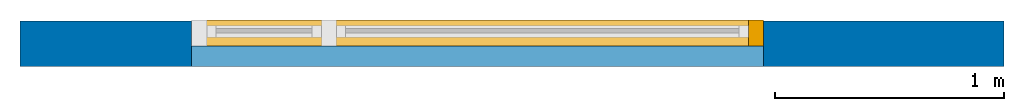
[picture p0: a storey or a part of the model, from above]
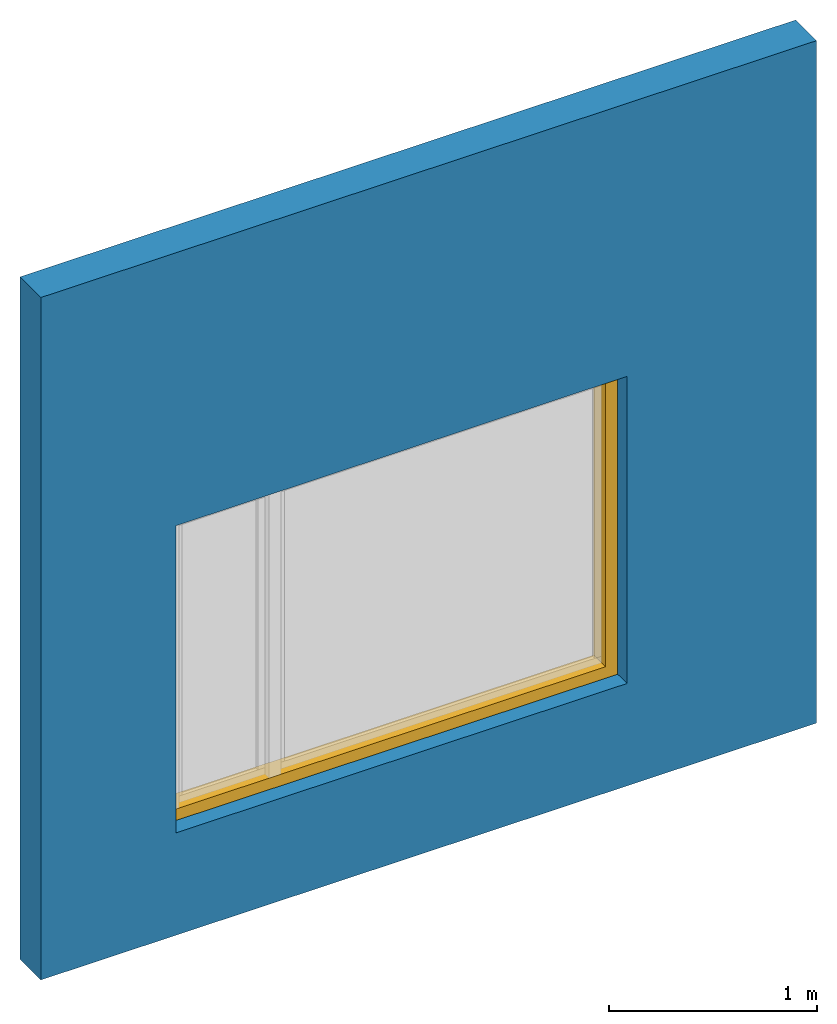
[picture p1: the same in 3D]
Properties of the parts of a building model (IFC2X3)

# File
Description: ViewDefinition [CoordinationView_V2.0]
Time: 2013-11-18T13:30:34
Written by: The EXPRESS Data Manager Version 5.01.0100.02.64mod : 6 Jun 2012
Made in: 20130308_1515(x64) - Exporter 3.5.0.0 - Alternate UI 2.5.0.0
Comment: STEP Physical File produced by: The EXPRESS Data Manager Version 5.01.0100.02.64mod : 6 Jun 2012 * Module: EDMstepFileFactory/EDMstandAlone * Creation date: Mon Nov 18 13:30:34 2013 * Host: MDR_LPTP_BTO * Database: C:\Users\Martijn\AppData\Local\Temp\{63A8A632-8D2A-48E5-82E8-79CE2EC71F87}\ifc * Database version: 5507 * Database creation date: Mon Nov 18 13:30:31 2013 * Schema: IFC2X3 * Model: DataRepository.ifc * Model creation date: Mon Nov 18 13:30:31 2013 * Header model: DataRepository.ifc_HeaderModel * Header model creation date: Mon Nov 18 13:30:31 2013 * EDMuser: sdai-user * EDMgroup: sdai-group * License ID and type: 5605 : Permanent license. Expiry date: * EDMstepFileFactory options: 020000

# IfcProject
LongName: E:\MdR Advies\Google Drive\005_Dropbox\Dropbox\RevitGG\RevitGG - DRS\WIP v1.1\test_export_window.ifc

# IfcSite, Default
RefLatitude: 42, 24, 53, 508911; RefLongitude: -71, -15, -29, -58837; RefElevation: 0 mm

# IfcBuilding
Pset_BuildingCommon - NumberOfStoreys: 1

# IfcBuildingStorey, Level 1
LongName: Level 1; Elevation: 0 mm

# IfcBuildingElementProxy: 30_GM_LB_bovendorpel, 30_GM_LB_bovendorpel:30_GM_LB_bovendorpel:16037
In: Level 1
Pset_BuildingElementProxyCommon - Reference: 30_GM_LB_bovendorpel

# IfcBuildingElementProxy: 30_GM_LB_raamhout (8)
In: Level 1
Pset_BuildingElementProxyCommon - Reference: 30_GM_LB_raamhout
Name (30_GM_LB_raamhout:30_GM_LB_raamhout:...)
16042
16043
16044
16045
16047
16048
16049
16050

# IfcBuildingElementProxy: 30_GM_LB_tussenstijl, 30_GM_LB_tussenstijl:30_GM_LB_tussenstijl:16039
In: Level 1
Pset_BuildingElementProxyCommon - Reference: 30_GM_LB_tussenstijl

# IfcBuildingElementProxy: 30_GM_LB_zijstijl_links, 30_GM_LB_zijstijl_links:30_GM_LB_zijstijl_links:16038
In: Level 1
Pset_BuildingElementProxyCommon - Reference: 30_GM_LB_zijstijl_links

# IfcWallStandardCase: Basic Wall:Wall 1, Basic Wall:Wall 1:2292
In: Level 1
Type - PredefinedType: STANDARD; Material: Default Wall 200 mm
Pset_WallCommon - Reference: Wall 1; LoadBearing: no; ExtendToStructure: no; IsExternal: yes
PSet_COBIE - NominalLength: 4300; NominalWidth: 200

# IfcWindow: 31_WI_A1B1, 31_WI_A1B1:31_WI_A1B1:16035
In: Level 1
Type - ParameterTakesPrecedence: no; Sizeable: no
OverallHeight: 1800 mm; OverallWidth: 2500 mm
Pset_WindowCommon - Reference: 31_WI_A1B1; IsExternal: yes

# IfcWindow: draai_links, 30_WI_vulling:draai_links:16041
In: Level 1
Type - ParameterTakesPrecedence: no; Sizeable: no; Material: Glass
OverallHeight: 54 mm; OverallWidth: 1799.5 mm
Pset_WindowCommon - Reference: draai_links; IsExternal: no

# IfcWindow: draai_rechts, 30_WI_vulling:draai_rechts:16040
In: Level 1
Type - ParameterTakesPrecedence: no; Sizeable: no; Material: Glass
OverallHeight: 54 mm; OverallWidth: 499.5 mm
Pset_WindowCommon - Reference: draai_rechts; IsExternal: no
